One B-rep face of a CAD part: STEP entity #81.
In plain terms, the planar face has unit normal (1, 0, 0).
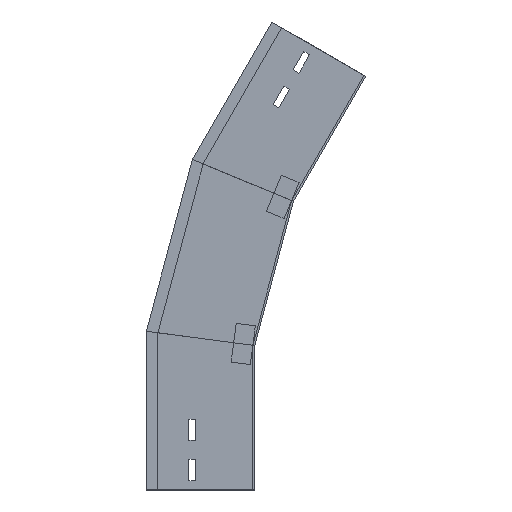
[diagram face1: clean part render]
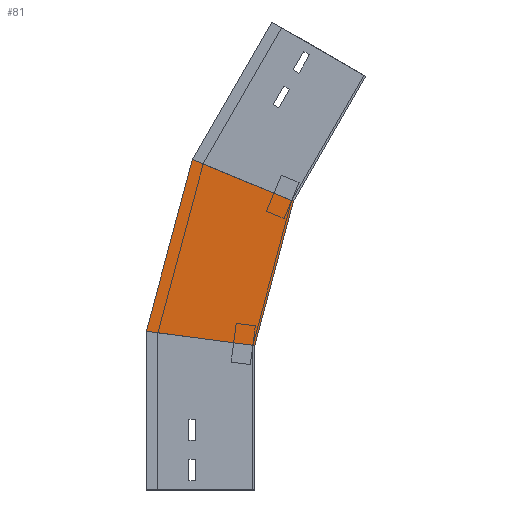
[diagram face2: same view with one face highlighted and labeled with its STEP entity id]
Its self-contained STEP definition (entity closure, numbers rounded to 3 decimals):
#81 = ADVANCED_FACE ( 'NONE', ( #935 ), #833, .T. ) ;
#98 = CARTESIAN_POINT ( 'NONE',  ( 0., 112.5, 164.811 ) ) ;
#102 = CARTESIAN_POINT ( 'NONE',  ( 0., -60.785, 291.157 ) ) ;
#176 = CARTESIAN_POINT ( 'NONE',  ( 0., 4.243, 134.167 ) ) ;
#207 = VECTOR ( 'NONE', #1421, 1000. ) ;
#273 = VERTEX_POINT ( 'NONE', #720 ) ;
#318 = LINE ( 'NONE', #772, #207 ) ;
#356 = LINE ( 'NONE', #102, #1076 ) ;
#491 = ORIENTED_EDGE ( 'NONE', *, *, #1347, .T. ) ;
#537 = ORIENTED_EDGE ( 'NONE', *, *, #566, .T. ) ;
#562 = DIRECTION ( 'NONE',  ( 0., -0.924, -0.383 ) ) ;
#566 = EDGE_CURVE ( 'NONE', #273, #674, #356, .T. ) ;
#649 = DIRECTION ( 'NONE',  ( 0., -0.259, 0.966 ) ) ;
#674 = VERTEX_POINT ( 'NONE', #1310 ) ;
#720 = CARTESIAN_POINT ( 'NONE',  ( 0., 64.716, 343.142 ) ) ;
#740 = EDGE_CURVE ( 'NONE', #1443, #674, #1199, .T. ) ;
#772 = CARTESIAN_POINT ( 'NONE',  ( 0., -19.411, 147.444 ) ) ;
#832 = AXIS2_PLACEMENT_3D ( 'NONE', #1152, #960, #1286 ) ;
#833 = PLANE ( 'NONE',  #832 ) ;
#868 = ORIENTED_EDGE ( 'NONE', *, *, #1187, .F. ) ;
#933 = CARTESIAN_POINT ( 'NONE',  ( 0., 112.909, 163.284 ) ) ;
#935 = FACE_OUTER_BOUND ( 'NONE', #1074, .T. ) ;
#960 = DIRECTION ( 'NONE',  ( 1., 0., 0. ) ) ;
#1074 = EDGE_LOOP ( 'NONE', ( #491, #537, #1189, #868 ) ) ;
#1076 = VECTOR ( 'NONE', #562, 1000. ) ;
#1121 = CARTESIAN_POINT ( 'NONE',  ( 0., 0., 150. ) ) ;
#1152 = CARTESIAN_POINT ( 'NONE',  ( 0., 4.243, 134.167 ) ) ;
#1170 = LINE ( 'NONE', #933, #1366 ) ;
#1187 = EDGE_CURVE ( 'NONE', #1428, #1443, #318, .T. ) ;
#1189 = ORIENTED_EDGE ( 'NONE', *, *, #740, .F. ) ;
#1199 = LINE ( 'NONE', #176, #1320 ) ;
#1286 = DIRECTION ( 'NONE',  ( 0., 0., -1. ) ) ;
#1310 = CARTESIAN_POINT ( 'NONE',  ( 0., -40.117, 299.719 ) ) ;
#1320 = VECTOR ( 'NONE', #649, 1000. ) ;
#1347 = EDGE_CURVE ( 'NONE', #1428, #273, #1170, .T. ) ;
#1366 = VECTOR ( 'NONE', #1415, 1000. ) ;
#1415 = DIRECTION ( 'NONE',  ( 0., -0.259, 0.966 ) ) ;
#1421 = DIRECTION ( 'NONE',  ( 0., -0.991, -0.131 ) ) ;
#1428 = VERTEX_POINT ( 'NONE', #98 ) ;
#1443 = VERTEX_POINT ( 'NONE', #1121 ) ;
